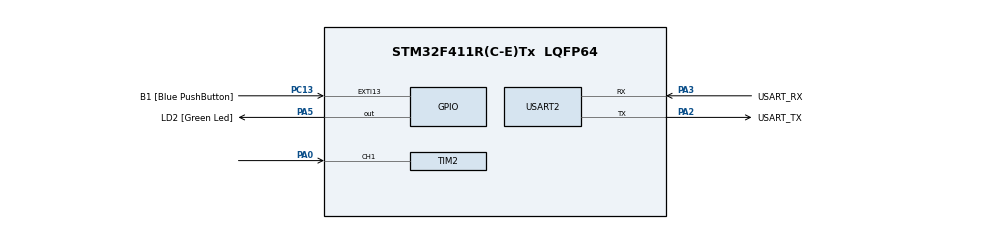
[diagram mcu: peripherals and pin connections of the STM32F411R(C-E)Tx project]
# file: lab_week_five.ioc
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Mcu.Family=STM32F4
PC15-OSC32_OUT.Mode=LSE-External-Oscillator
Dma.TIM2_CH1.0.MemInc=DMA_MINC_ENABLE
RCC.CortexFreq_Value=84000000
TIM2.Channel-Input_Capture1_from_TI1=TIM_CHANNEL_1
PC13-ANTI_TAMP.GPIO_Label=B1 [Blue PushButton]
VP_TIM5_VS_OPM.Mode=OPM_bit
PA14.GPIO_Label=TCK
PH1\ -\ OSC_OUT.Mode=HSE-External-Clock-Source
Dma.TIM2_CH1.0.Instance=DMA1_Stream5
RCC.APB1CLKDivider=RCC_HCLK_DIV2
PC14-OSC32_IN.Signal=RCC_OSC32_IN
RCC.SYSCLKSource=RCC_SYSCLKSOURCE_PLLCLK
ProjectManager.StackSize=0x400
PA0-WKUP.Signal=S_TIM2_CH1_ETR
PA3.Mode=Asynchronous
PA13.Signal=SYS_JTMS-SWDIO
PH0\ -\ OSC_IN.Mode=HSE-External-Clock-Source
PH0\ -\ OSC_IN.Signal=RCC_OSC_IN
ProjectManager.TargetToolchain=STM32CubeIDE
NVIC.DMA1_Stream5_IRQn=true\:0\:0\:false\:false\:true\:false\:true
NVIC.TIM5_IRQn=true\:0\:0\:false\:false\:true\:true\:true
RCC.HCLKFreq_Value=84000000
RCC.APB2TimFreq_Value=84000000
TIM2.ICFilter_CH1=2
PC15-OSC32_OUT.Signal=RCC_OSC32_OUT
RCC.AHBFreq_Value=84000000
PA5.Signal=GPIO_Output
RCC.HSE_VALUE=8000000
PH1\ -\ OSC_OUT.Signal=RCC_OSC_OUT
board=NUCLEO-F411RE
PC13-ANTI_TAMP.Signal=GPXTI13
RCC.VCOOutputFreq_Value=336000000
RCC.APB2Freq_Value=84000000
Dma.TIM2_CH1.0.Priority=DMA_PRIORITY_LOW
PC14-OSC32_IN.Mode=LSE-External-Oscillator
VP_TIM2_VS_ClockSourceINT.Mode=Internal
PA14.Mode=Serial_Wire
PA13.Mode=Serial_Wire
Mcu.Name=STM32F411R(C-E)Tx
PA2.Signal=USART2_TX
PA13.GPIO_Label=TMS
RCC.FLatency-AdvancedSettings=FLASH_LATENCY_2
RCC.48MHZClocksFreq_Value=84000000
PB3.Signal=SYS_JTDO-SWO
RCC.SYSCLKFreq_VALUE=84000000
Mcu.Package=LQFP64
Dma.TIM2_CH1.0.Mode=DMA_CIRCULAR
TIM2.Prescaler=99
Dma.TIM2_CH1.0.FIFOMode=DMA_FIFOMODE_DISABLE
PA5.GPIO_Label=LD2 [Green Led]
TIM5.Prescaler=99
USART2.VirtualMode=VM_ASYNC
PC13-ANTI_TAMP.GPIO_ModeDefaultEXTI=GPIO_MODE_IT_FALLING
PA2.GPIO_Label=USART_TX
Dma.TIM2_CH1.0.MemDataAlignment=DMA_MDATAALIGN_WORD
SH.S_TIM2_CH1_ETR.0=TIM2_CH1,Input_Capture1_from_TI1
PA14.Signal=SYS_JTCK-SWCLK
ProjectManager.HeapSize=0x200
Dma.TIM2_CH1.0.PeriphDataAlignment=DMA_PDATAALIGN_WORD
RCC.HSI_VALUE=16000000
RCC.PLLP=RCC_PLLP_DIV4
NVIC.PriorityGroup=NVIC_PRIORITYGROUP_0
RCC.PLLN=336
RCC.APB1TimFreq_Value=84000000
PA2.Mode=Asynchronous
Dma.Request0=TIM2_CH1
RCC.APB1Freq_Value=42000000
Dma.TIM2_CH1.0.Direction=DMA_PERIPH_TO_MEMORY
Dma.TIM2_CH1.0.PeriphInc=DMA_PINC_DISABLE
PA3.GPIO_Label=USART_RX
PA3.Signal=USART2_RX
PB3.GPIO_Label=SWO

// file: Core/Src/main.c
/* USER CODE BEGIN Header */
/**
  ******************************************************************************
  * @file           : main.c
  * @brief          : Main program body
  ******************************************************************************
  * @attention
  *
  * <h2><center>&copy; Copyright (c) 2021 STMicroelectronics.
  * All rights reserved.</center></h2>
  *
  * This software component is licensed by ST under BSD 3-Clause license,
  * the "License"; You may not use this file except in compliance with the
  * License. You may obtain a copy of the License at:
  *                        opensource.org/licenses/BSD-3-Clause
  *
  ******************************************************************************
  */
/* USER CODE END Header */
#include "main.h"

/* USER CODE BEGIN PD */
#define CAPTURENUM 16
/* USER CODE END PD */

TIM_HandleTypeDef htim2;
TIM_HandleTypeDef htim5;
DMA_HandleTypeDef hdma_tim2_ch1;

UART_HandleTypeDef huart2;

/* USER CODE BEGIN PV */
//DMA Buffer
uint32_t capturedata[CAPTURENUM]={0};
//diff time
int32_t DiffTime[CAPTURENUM-1]={0};
//Mean difftime
float MeanTime=0;
float frequency=0;
int RPM=0;

uint64_t _micros=0;

/* USER CODE END PV */

void SystemClock_Config(void);
static void MX_GPIO_Init(void);
static void MX_DMA_Init(void);
static void MX_USART2_UART_Init(void);
static void MX_TIM2_Init(void);
static void MX_TIM5_Init(void);
/* USER CODE BEGIN PFP */
void encoderSpeedReaderCycle();
void frequencytoRPM();
uint64_t micros();

/* USER CODE END PFP */

int main(void)
{

  /* MCU Configuration--------------------------------------------------------*/

  /* Reset of all peripherals, Initializes the Flash interface and the Systick. */
  HAL_Init();

  /* Configure the system clock */
  SystemClock_Config();

  /* Initialize all configured peripherals */
  MX_GPIO_Init();
  MX_DMA_Init();
  MX_USART2_UART_Init();
  MX_TIM2_Init();
  MX_TIM5_Init();
  /* USER CODE BEGIN 2 */
  	  //start Microsec timer
  HAL_TIM_Base_Start_IT(&htim5);

  //start Input capture in DMA
  HAL_TIM_Base_Start(&htim2);
  HAL_TIM_IC_Start_DMA(&htim2, TIM_CHANNEL_1, (uint32_t*) &capturedata, CAPTURENUM);
  uint64_t timestamp=0;

  /* USER CODE END 2 */

  /* Infinite loop */
  /* USER CODE BEGIN WHILE */
  while (1)
  {
	  //read Time of encoder
	  frequencytoRPM();
	  encoderSpeedReaderCycle();
	  if(micros()-timestamp>100000)//uS
	  {
		  timestamp = micros();
		  HAL_GPIO_TogglePin(LD2_GPIO_Port, LD2_Pin);
	  }
    /* USER CODE END WHILE */

  }
}

void SystemClock_Config(void)
{
  RCC_OscInitTypeDef RCC_OscInitStruct = {0};
  RCC_ClkInitTypeDef RCC_ClkInitStruct = {0};

  /** Configure the main internal regulator output voltage
  */
  __HAL_RCC_PWR_CLK_ENABLE();
  __HAL_PWR_VOLTAGESCALING_CONFIG(PWR_REGULATOR_VOLTAGE_SCALE1);
  /** Initializes the RCC Oscillators according to the specified parameters
  * in the RCC_OscInitTypeDef structure.
  */
  RCC_OscInitStruct.OscillatorType = RCC_OSCILLATORTYPE_HSI;
  RCC_OscInitStruct.HSIState = RCC_HSI_ON;
  RCC_OscInitStruct.HSICalibrationValue = RCC_HSICALIBRATION_DEFAULT;
  RCC_OscInitStruct.PLL.PLLState = RCC_PLL_ON;
  RCC_OscInitStruct.PLL.PLLSource = RCC_PLLSOURCE_HSI;
  RCC_OscInitStruct.PLL.PLLM = 8;
  RCC_OscInitStruct.PLL.PLLN = 100;
  RCC_OscInitStruct.PLL.PLLP = RCC_PLLP_DIV2;
  RCC_OscInitStruct.PLL.PLLQ = 4;
  if (HAL_RCC_OscConfig(&RCC_OscInitStruct) != HAL_OK)
  {
    Error_Handler();
  }
  /** Initializes the CPU, AHB and APB buses clocks
  */
  RCC_ClkInitStruct.ClockType = RCC_CLOCKTYPE_HCLK|RCC_CLOCKTYPE_SYSCLK
                              |RCC_CLOCKTYPE_PCLK1|RCC_CLOCKTYPE_PCLK2;
  RCC_ClkInitStruct.SYSCLKSource = RCC_SYSCLKSOURCE_PLLCLK;
  RCC_ClkInitStruct.AHBCLKDivider = RCC_SYSCLK_DIV1;
  RCC_ClkInitStruct.APB1CLKDivider = RCC_HCLK_DIV2;
  RCC_ClkInitStruct.APB2CLKDivider = RCC_HCLK_DIV1;

  if (HAL_RCC_ClockConfig(&RCC_ClkInitStruct, FLASH_LATENCY_3) != HAL_OK)
  {
    Error_Handler();
  }
}

static void MX_TIM2_Init(void)
{

  TIM_ClockConfigTypeDef sClockSourceConfig = {0};
  TIM_MasterConfigTypeDef sMasterConfig = {0};
  TIM_IC_InitTypeDef sConfigIC = {0};

  htim2.Instance = TIM2;
  htim2.Init.Prescaler = 99;
  htim2.Init.CounterMode = TIM_COUNTERMODE_UP;
  htim2.Init.Period = 4294967295;
  htim2.Init.ClockDivision = TIM_CLOCKDIVISION_DIV1;
  htim2.Init.AutoReloadPreload = TIM_AUTORELOAD_PRELOAD_DISABLE;
  if (HAL_TIM_Base_Init(&htim2) != HAL_OK)
  {
    Error_Handler();
  }
  sClockSourceConfig.ClockSource = TIM_CLOCKSOURCE_INTERNAL;
  if (HAL_TIM_ConfigClockSource(&htim2, &sClockSourceConfig) != HAL_OK)
  {
    Error_Handler();
  }
  if (HAL_TIM_IC_Init(&htim2) != HAL_OK)
  {
    Error_Handler();
  }
  sMasterConfig.MasterOutputTrigger = TIM_TRGO_RESET;
  sMasterConfig.MasterSlaveMode = TIM_MASTERSLAVEMODE_DISABLE;
  if (HAL_TIMEx_MasterConfigSynchronization(&htim2, &sMasterConfig) != HAL_OK)
  {
    Error_Handler();
  }
  sConfigIC.ICPolarity = TIM_INPUTCHANNELPOLARITY_RISING;
  sConfigIC.ICSelection = TIM_ICSELECTION_DIRECTTI;
  sConfigIC.ICPrescaler = TIM_ICPSC_DIV1;
  sConfigIC.ICFilter = 2;
  if (HAL_TIM_IC_ConfigChannel(&htim2, &sConfigIC, TIM_CHANNEL_1) != HAL_OK)
  {
    Error_Handler();
  }

}

static void MX_TIM5_Init(void)
{

  htim5.Instance = TIM5;
  htim5.Init.Prescaler = 99;
  htim5.Init.CounterMode = TIM_COUNTERMODE_UP;
  htim5.Init.Period = 4294967295;
  htim5.Init.ClockDivision = TIM_CLOCKDIVISION_DIV1;
  htim5.Init.AutoReloadPreload = TIM_AUTORELOAD_PRELOAD_DISABLE;
  if (HAL_TIM_OnePulse_Init(&htim5, TIM_OPMODE_SINGLE) != HAL_OK)
  {
    Error_Handler();
  }

}

static void MX_USART2_UART_Init(void)
{

  huart2.Instance = USART2;
  huart2.Init.BaudRate = 115200;
  huart2.Init.WordLength = UART_WORDLENGTH_8B;
  huart2.Init.StopBits = UART_STOPBITS_1;
  huart2.Init.Parity = UART_PARITY_NONE;
  huart2.Init.Mode = UART_MODE_TX_RX;
  huart2.Init.HwFlowCtl = UART_HWCONTROL_NONE;
  huart2.Init.OverSampling = UART_OVERSAMPLING_16;
  if (HAL_UART_Init(&huart2) != HAL_OK)
  {
    Error_Handler();
  }

}

static void MX_DMA_Init(void)
{

  /* DMA controller clock enable */
  __HAL_RCC_DMA1_CLK_ENABLE();

  /* DMA interrupt init */
  /* DMA1_Stream5_IRQn interrupt configuration */
  HAL_NVIC_SetPriority(DMA1_Stream5_IRQn, 0, 0);
  HAL_NVIC_EnableIRQ(DMA1_Stream5_IRQn);

}

static void MX_GPIO_Init(void)
{
  GPIO_InitTypeDef GPIO_InitStruct = {0};

  /* GPIO Ports Clock Enable */
  __HAL_RCC_GPIOC_CLK_ENABLE();
  __HAL_RCC_GPIOH_CLK_ENABLE();
  __HAL_RCC_GPIOA_CLK_ENABLE();
  __HAL_RCC_GPIOB_CLK_ENABLE();

  /*Configure GPIO pin Output Level */
  HAL_GPIO_WritePin(LD2_GPIO_Port, LD2_Pin, GPIO_PIN_RESET);

  /*Configure GPIO pin : B1_Pin */
  GPIO_InitStruct.Pin = B1_Pin;
  GPIO_InitStruct.Mode = GPIO_MODE_IT_FALLING;
  GPIO_InitStruct.Pull = GPIO_NOPULL;
  HAL_GPIO_Init(B1_GPIO_Port, &GPIO_InitStruct);

  /*Configure GPIO pin : LD2_Pin */
  GPIO_InitStruct.Pin = LD2_Pin;
  GPIO_InitStruct.Mode = GPIO_MODE_OUTPUT_PP;
  GPIO_InitStruct.Pull = GPIO_NOPULL;
  GPIO_InitStruct.Speed = GPIO_SPEED_FREQ_LOW;
  HAL_GPIO_Init(LD2_GPIO_Port, &GPIO_InitStruct);

}

/* USER CODE BEGIN 4 */
void encoderSpeedReaderCycle() {
	//get DMA Position form number of data
	uint32_t CapPos =CAPTURENUM -  __HAL_DMA_GET_COUNTER(htim2.hdma[TIM_DMA_ID_CC1]);
	uint32_t sum = 0 ;

	//calculate diff from all buffer
	for(register int i=0 ;i < CAPTURENUM-1;i++)
	{
		DiffTime[i]  = capturedata[(CapPos+1+i)%CAPTURENUM]-capturedata[(CapPos+i)%CAPTURENUM];
		//time never go back, but timer can over flow , conpensate that
		if (DiffTime[i] <0)
		{
			DiffTime[i]+=4294967295;
		}
		//Sum all 15 Diff
		sum += DiffTime[i];
	}

	//mean all 15 Diff
	MeanTime =sum / (float)(CAPTURENUM-1);
}
uint64_t micros()
{
	return _micros+htim5.Instance->CNT;
}
//interupt
void HAL_TIM_PeriodElapsedHalfCpltCallback(TIM_HandleTypeDef *htim)
{
	if(htim == &htim5)
	 {
		 _micros +=4294967295;
	 }
}
void frequencytoRPM()
{
	frequency=1/(MeanTime*0.000001);
	RPM=(frequency*60)/(12*64);
}

/* USER CODE END 4 */

void Error_Handler(void)
{
  __disable_irq();
  while (1)
  {
  }
}

/************************ (C) COPYRIGHT STMicroelectronics *****END OF FILE****/
